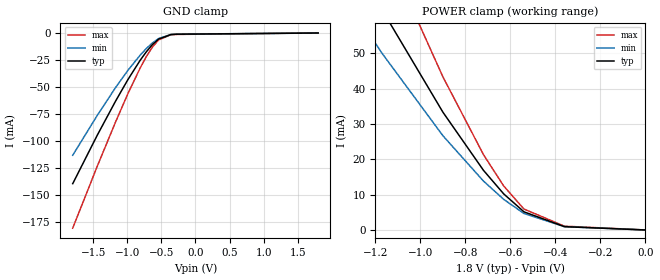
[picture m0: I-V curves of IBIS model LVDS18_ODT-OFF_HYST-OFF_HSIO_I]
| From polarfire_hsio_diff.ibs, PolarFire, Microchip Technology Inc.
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|   Model LVDS18_ODT-OFF_HYST-OFF_HSIO_I
[Model]   LVDS18_ODT-OFF_HYST-OFF_HSIO_I
Model_type   Input
Vinl =   1.125
Vinh =   1.375
|   typ   min   max
C_comp_pullup   1.335e-12   1.335e-12   1.380e-12
C_comp_pulldown  1.335e-12   1.335e-12   1.380e-12
[Temperature Range]  25C   100C   -40C
[Voltage Range]  1.8   1.71   1.89
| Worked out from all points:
|   GND clamp passes 1 mA (typ) near -0.35 V on its own axis
|   POWER clamp passes 1 mA (typ) near -0.36 V on its own axis
[GND_clamp]
|Voltage   I(typ)   I(min)   I(max)
-1.8V     -139.5mA   -113.1mA   -180.8mA
-1.44V    -94.51mA   -76.11mA   -123.3mA
-1.17V    -62.68mA   -50.12mA   -81.99mA
-990mV    -42.83mA   -34.24mA   -55.88mA
-810mV    -24.87mA   -20.1mA    -31.99mA
-720mV    -17.03mA   -13.98mA   -21.49mA
-630mV    -10.33mA   -8.777mA   -12.59mA
-540mV    -5.237mA   -4.754mA   -6.05mA
-360mV    -1.035mA   -1.014mA   -1.194mA
-270mV    -719.6uA   -615.9uA   -922.4uA
1.8V      403.5uA    340.2uA    502.7uA
[POWER_clamp]
|Voltage   I(typ)   I(min)   I(max)
-1.8V     139.3mA    113.1mA    180.4mA
-1.44V    94.25mA    76.04mA    122.7mA
-1.17V    62.28mA    49.98mA    81.53mA
-900mV    33.34mA    26.68mA    43.34mA
-720mV    16.9mA     13.85mA    21.35mA
-630mV    10.22mA    8.671mA    12.46mA
-540mV    5.136mA    4.664mA    5.927mA
-360mV    939.1uA    931.1uA    1.075mA
0V        0A         0A         0A
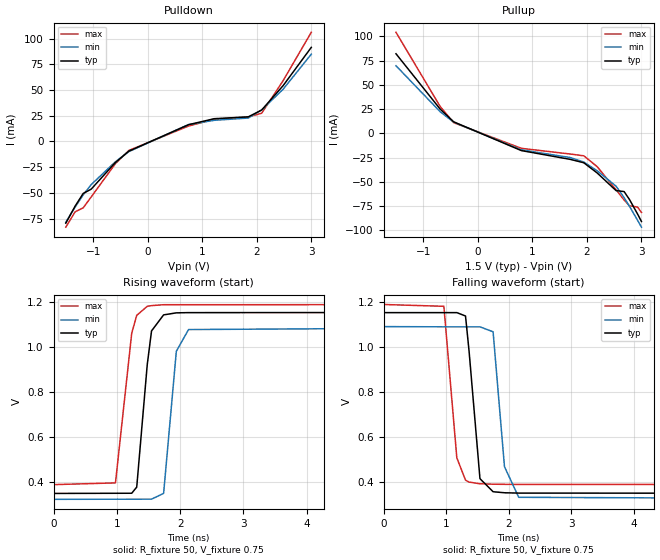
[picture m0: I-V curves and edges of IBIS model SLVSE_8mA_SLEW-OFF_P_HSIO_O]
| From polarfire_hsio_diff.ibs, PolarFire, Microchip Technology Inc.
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|   Model SLVSE_8mA_SLEW-OFF_P_HSIO_O
[Model]   SLVSE_8mA_SLEW-OFF_P_HSIO_O
Model_type   Output
Polarity   Non-Inverting
Enable   Active-High
Vmeas =   0.2
Cref =   5p
Rref =   100
|   typ   min   max
C_comp_pullup   1.335e-12   1.335e-12   1.380e-12
C_comp_pulldown  1.335e-12   1.335e-12   1.380e-12
[Temperature Range]  25C   100C   -40C
[Voltage Range]  1.5   1.425   1.575
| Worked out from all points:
|   slope of the pulldown table from 0 to 0.225 V, typ, clamps not added: 41.3 ohm
|   slope of the pullup table from 0 to 0.225 V, typ, clamps not added: 41.3 ohm
|   rising waveform, R_fixture 50, V_fixture 0.75: 20-80 % time 141ps typ, 129ps min, 175ps max; typ from 0.35 V to 1.15 V
|   falling waveform, R_fixture 50, V_fixture 0.75: 20-80 % time 120ps typ, 125ps min, 129ps max; typ from 1.15 V to 0.35 V
[Pullup]
| Voltage   I(typ)   I(min)   I(max)
-1.5V     82.17mA    69.83mA    104.3mA
-689.1mV  25.02mA    22.3mA     27.64mA
-443mV    11.95mA    11.6mA     11.09mA
796.9mV   -17.71mA   -16.94mA   -15.39mA
1.697V    -26.83mA   -24.95mA   -21.3mA
1.943V    -30.3mA    -29.56mA   -23.13mA
2.189V    -40.87mA   -38.59mA   -34.37mA
2.534V    -58.98mA   -54.43mA   -58.14mA
2.681V    -60mA      -66.28mA   -68.66mA
2.78V     -68.2mA    -75.24mA   -74.75mA
2.927V    -83.06mA   -89.5mA    -75.97mA
3V        -90.94mA   -96.74mA   -81.58mA
[Pulldown]
| Voltage   I(typ)   I(min)   I(max)
-1.5V     -79.31mA   -78.36mA   -83.18mA
-1.329V   -62.78mA   -63.64mA   -68.26mA
-1.181V   -50.43mA   -51.83mA   -64.43mA
-1.034V   -46.25mA   -41.83mA   -53.8mA
-590.6mV  -20.36mA   -19.67mA   -21.51mA
-344.5mV  -9.397mA   -9.824mA   -8.7mA
750mV     16.29mA    16.47mA    15mA
1.219V    22.12mA    20.56mA    21.61mA
1.845V    23.91mA    22.78mA    23.84mA
2.091V    30.58mA    30.69mA    27.43mA
2.484V    54.25mA    50.76mA    59.11mA
3V        91.37mA    84.77mA    106mA
[Ramp]
dV/dt_r   0.48125/0.14101n  0.459297/0.128881n  0.478971/0.174914n
dV/dt_f   0.481266/0.119895n  0.459316/0.125187n  0.478979/0.128803n
R_load = 50
[Rising Waveform]
R_fixture = 50
V_fixture = 0.75
V_fixture_min = 0.7125
V_fixture_max = 0.7875
| Time   V(typ)   V(min)   V(max)
0s        350mV      323.9mV    389mV
979ps     350.7mV    324.4mV    396.7mV
1.236ns   350.9mV    324.5mV    1.06V
1.315ns   378.1mV    324.5mV    1.139V
1.481ns   919.7mV    324.6mV    1.179V
1.549ns   1.07V      324.6mV    1.182V
1.74ns    1.141V     350.3mV    1.186V
1.941ns   1.15V      980mV      1.186V
2.134ns   1.151V     1.076V     1.186V
10ns      1.152V     1.089V     1.187V
[Falling Waveform]
R_fixture = 50
V_fixture = 0.75
V_fixture_min = 0.7125
V_fixture_max = 0.7875
| Time   V(typ)   V(min)   V(max)
0s        1.152V     1.09V      1.188V
962ps     1.152V     1.089V     1.18V
1.169ns   1.152V     1.089V     508.2mV
1.308ns   1.137V     1.089V     409.2mV
1.365ns   981mV      1.089V     400.5mV
1.539ns   415.7mV    1.089V     393.2mV
1.749ns   357.8mV    1.067V     391.2mV
1.931ns   353.2mV    468.9mV    390.6mV
2.159ns   351.8mV    333.1mV    390.3mV
10ns      350.4mV    324.1mV    389.5mV
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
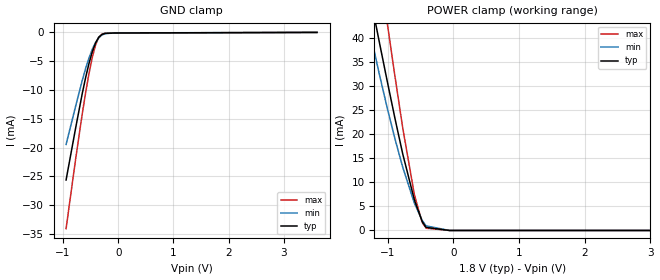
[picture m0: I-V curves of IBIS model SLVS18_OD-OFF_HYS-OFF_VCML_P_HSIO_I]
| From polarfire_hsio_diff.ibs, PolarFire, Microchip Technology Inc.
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|   Model SLVS18_OD-OFF_HYS-OFF_VCML_P_HSIO_I
[Model]   SLVS18_OD-OFF_HYS-OFF_VCML_P_HSIO_I
Model_type   Input
Vinl =   0.275
Vinh =   0.525
|   typ   min   max
C_comp_pullup   1.335e-12   1.335e-12   1.380e-12
C_comp_pulldown  1.335e-12   1.335e-12   1.380e-12
[Temperature Range]  25C   100C   -40C
[Voltage Range]  1.8   1.71   1.89
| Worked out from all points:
|   GND clamp passes 1 mA (typ) near -0.36 V on its own axis
|   POWER clamp passes 1 mA (typ) near -0.43 V on its own axis
[GND Clamp]
| Voltage   I(typ)   I(min)   I(max)
-945mV    -25.62mA   -19.44mA   -34.06mA
-767.8mV  -16.39mA   -12.64mA   -21.7mA
-649.7mV  -10.5mA    -8.252mA   -13.99mA
-590.6mV  -7.834mA   -6.26mA    -10.45mA
-531.6mV  -5.448mA   -4.48mA    -7.226mA
-472.5mV  -3.431mA   -2.972mA   -4.435mA
-413.4mV  -1.876mA   -1.787mA   -2.246mA
-354.4mV  -855.7uA   -955.9uA   -855.1uA
-295.3mV  -345.4uA   -461.1uA   -286.1uA
-236.2mV  -166.7uA   -223.3uA   -156.7uA
-59.06mV  -101uA     -89.11uA   -123.3uA
3.6V      0A         0A         0A
[POWER Clamp]
| Voltage   I(typ)   I(min)   I(max)
-1.8V     93.14mA    78.03mA    128.6mA
-1.358V   55.63mA    47.39mA    74.97mA
-1.24V    47.17mA    39.71mA    64.78mA
-1.122V   39.03mA    32.38mA    54.26mA
-1.004V   31.04mA    25.47mA    43.14mA
-885.9mV  23.26mA    19.03mA    32mA
-767.8mV  15.89mA    13.14mA    21.28mA
-590.6mV  6.331mA    5.66mA     7.4mA
-472.5mV  1.865mA    2.087mA    1.673mA
-413.4mV  646.4uA    961.3uA    469.5uA
-59.06mV  4uA        4.526uA    5.16uA
3.6V      0A         0A         0A
